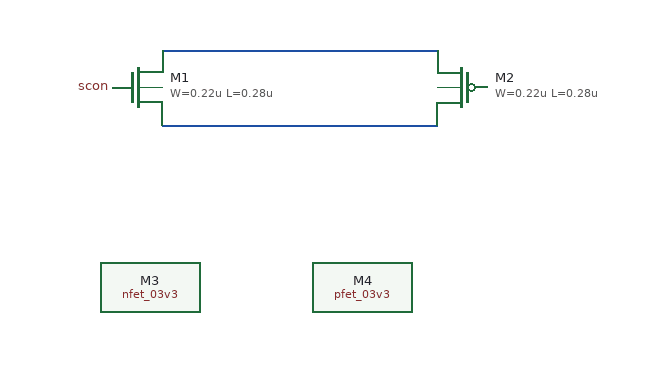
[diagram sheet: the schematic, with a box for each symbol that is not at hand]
v {xschem version=3.4.7 file_version=1.2}
G {}
K {}
V {}
S {}
E {}
N 170 -100 390 -100 {lab=#net1}
N 170 -160 390 -160 {lab=#net2}
C {symbols/nfet_03v3.sym} 150 -130 0 0 {name=M1
L=0.28u
W=0.22u
nf=1
m=1
ad="'int((nf+1)/2) * W/nf * 0.18u'"
pd="'2*int((nf+1)/2) * (W/nf + 0.18u)'"
as="'int((nf+2)/2) * W/nf * 0.18u'"
ps="'2*int((nf+2)/2) * (W/nf + 0.18u)'"
nrd="'0.18u / W'" nrs="'0.18u / W'"
sa=0 sb=0 sd=0
model=nfet_03v3
spiceprefix=X
}
C {symbols/pfet_03v3.sym} 410 -130 0 1 {name=M2
L=0.28u
W=0.22u
nf=1
m=1
ad="'int((nf+1)/2) * W/nf * 0.18u'"
pd="'2*int((nf+1)/2) * (W/nf + 0.18u)'"
as="'int((nf+2)/2) * W/nf * 0.18u'"
ps="'2*int((nf+2)/2) * (W/nf + 0.18u)'"
nrd="'0.18u / W'" nrs="'0.18u / W'"
sa=0 sb=0 sd=0
model=pfet_03v3
spiceprefix=X
}
C {devices/lab_pin.sym} 130 -130 0 0 {name=p5 sig_type=std_logic lab=scon}
C {symbols/nfet_03v3.sym} 160 30 0 0 {name=M3
L=0.28u
W=0.22u
nf=1
m=1
ad="'int((nf+1)/2) * W/nf * 0.18u'"
pd="'2*int((nf+1)/2) * (W/nf + 0.18u)'"
as="'int((nf+2)/2) * W/nf * 0.18u'"
ps="'2*int((nf+2)/2) * (W/nf + 0.18u)'"
nrd="'0.18u / W'" nrs="'0.18u / W'"
sa=0 sb=0 sd=0
model=nfet_03v3
spiceprefix=X
}
C {symbols/pfet_03v3.sym} 330 30 0 1 {name=M4
L=0.28u
W=0.22u
nf=1
m=1
ad="'int((nf+1)/2) * W/nf * 0.18u'"
pd="'2*int((nf+1)/2) * (W/nf + 0.18u)'"
as="'int((nf+2)/2) * W/nf * 0.18u'"
ps="'2*int((nf+2)/2) * (W/nf + 0.18u)'"
nrd="'0.18u / W'" nrs="'0.18u / W'"
sa=0 sb=0 sd=0
model=pfet_03v3
spiceprefix=X
}
